VERSION 5.7 ;
  NOWIREEXTENSIONATPIN ON ;
  DIVIDERCHAR "/" ;
  BUSBITCHARS "[]" ;
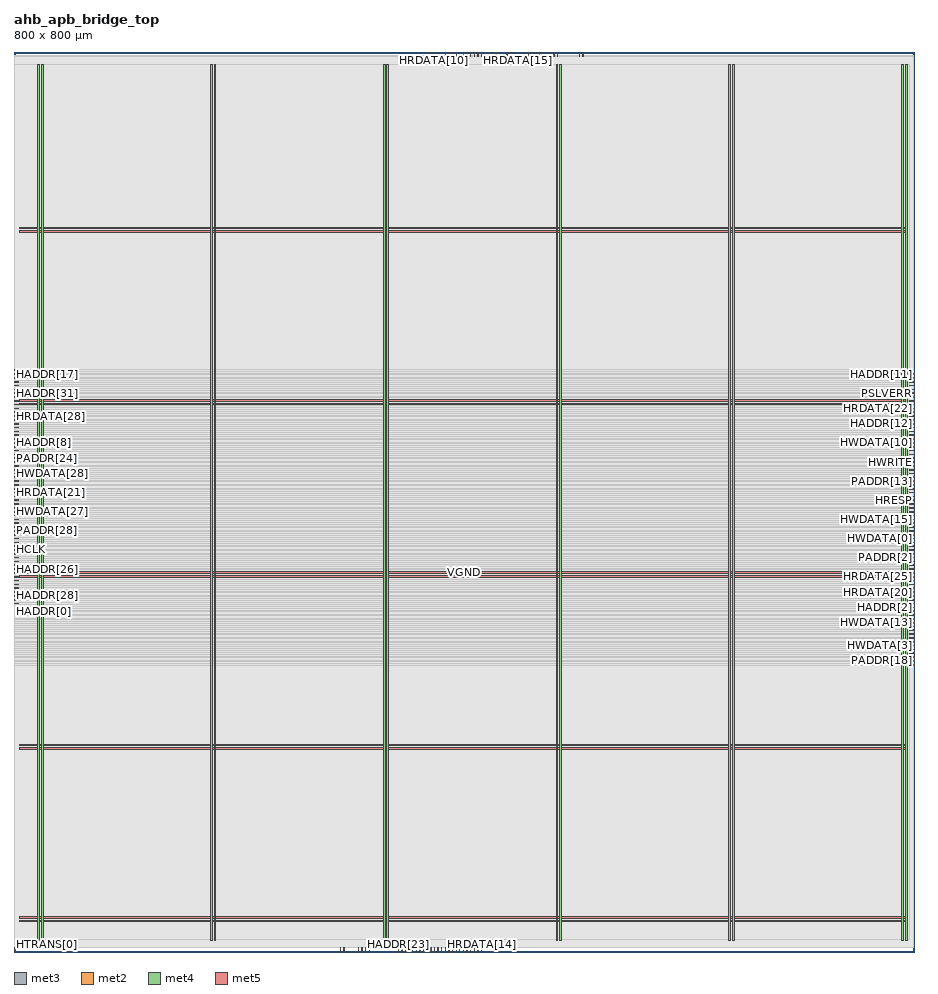
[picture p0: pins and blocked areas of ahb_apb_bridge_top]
MACRO ahb_apb_bridge_top
  CLASS BLOCK ;
  FOREIGN ahb_apb_bridge_top ;
  ORIGIN 0.000 0.000 ;
  SIZE 800.000 BY 800.000 ;
  PIN HADDR[0]
    DIRECTION INPUT ;
    USE SIGNAL ;
    ANTENNAGATEAREA 0.196500 ;
    PORT
      LAYER met3 ;
        RECT 0.000 309.440 4.000 310.040 ;
    END
  END HADDR[0]
  PIN HADDR[10]
    DIRECTION INPUT ;
    USE SIGNAL ;
    ANTENNAGATEAREA 0.196500 ;
    PORT
      LAYER met2 ;
        RECT 383.270 0.000 383.550 4.000 ;
    END
  END HADDR[10]
  PIN HADDR[11]
    DIRECTION INPUT ;
    USE SIGNAL ;
    ANTENNAGATEAREA 0.196500 ;
    PORT
      LAYER met3 ;
        RECT 796.000 513.440 800.000 514.040 ;
    END
  END HADDR[11]
  PIN HADDR[12]
    DIRECTION INPUT ;
    USE SIGNAL ;
    ANTENNAGATEAREA 0.196500 ;
    PORT
      LAYER met3 ;
        RECT 796.000 469.240 800.000 469.840 ;
    END
  END HADDR[12]
  PIN HADDR[13]
    DIRECTION INPUT ;
    USE SIGNAL ;
    ANTENNAGATEAREA 0.213000 ;
    PORT
      LAYER met2 ;
        RECT 463.770 796.000 464.050 800.000 ;
    END
  END HADDR[13]
  PIN HADDR[14]
    DIRECTION INPUT ;
    USE SIGNAL ;
    ANTENNAGATEAREA 0.196500 ;
    PORT
      LAYER met2 ;
        RECT 402.590 0.000 402.870 4.000 ;
    END
  END HADDR[14]
  PIN HADDR[15]
    DIRECTION INPUT ;
    USE SIGNAL ;
    ANTENNAGATEAREA 0.196500 ;
    PORT
      LAYER met3 ;
        RECT 0.000 516.840 4.000 517.440 ;
    END
  END HADDR[15]
  PIN HADDR[16]
    DIRECTION INPUT ;
    USE SIGNAL ;
    ANTENNAGATEAREA 0.196500 ;
    PORT
      LAYER met3 ;
        RECT 796.000 431.840 800.000 432.440 ;
    END
  END HADDR[16]
  PIN HADDR[17]
    DIRECTION INPUT ;
    USE SIGNAL ;
    ANTENNAGATEAREA 0.196500 ;
    PORT
      LAYER met3 ;
        RECT 0.000 513.440 4.000 514.040 ;
    END
  END HADDR[17]
  PIN HADDR[18]
    DIRECTION INPUT ;
    USE SIGNAL ;
    ANTENNAGATEAREA 0.196500 ;
    PORT
      LAYER met3 ;
        RECT 796.000 255.040 800.000 255.640 ;
    END
  END HADDR[18]
  PIN HADDR[19]
    DIRECTION INPUT ;
    USE SIGNAL ;
    ANTENNAGATEAREA 0.196500 ;
    PORT
      LAYER met3 ;
        RECT 796.000 278.840 800.000 279.440 ;
    END
  END HADDR[19]
  PIN HADDR[1]
    DIRECTION INPUT ;
    USE SIGNAL ;
    ANTENNAGATEAREA 0.196500 ;
    PORT
      LAYER met3 ;
        RECT 796.000 275.440 800.000 276.040 ;
    END
  END HADDR[1]
  PIN HADDR[20]
    DIRECTION INPUT ;
    USE SIGNAL ;
    ANTENNAGATEAREA 0.196500 ;
    PORT
      LAYER met2 ;
        RECT 370.390 796.000 370.670 800.000 ;
    END
  END HADDR[20]
  PIN HADDR[21]
    DIRECTION INPUT ;
    USE SIGNAL ;
    ANTENNAGATEAREA 0.196500 ;
    PORT
      LAYER met3 ;
        RECT 0.000 329.840 4.000 330.440 ;
    END
  END HADDR[21]
  PIN HADDR[22]
    DIRECTION INPUT ;
    USE SIGNAL ;
    ANTENNAGATEAREA 0.196500 ;
    PORT
      LAYER met3 ;
        RECT 796.000 309.440 800.000 310.040 ;
    END
  END HADDR[22]
  PIN HADDR[23]
    DIRECTION INPUT ;
    USE SIGNAL ;
    ANTENNAGATEAREA 0.196500 ;
    PORT
      LAYER met2 ;
        RECT 341.410 0.000 341.690 4.000 ;
    END
  END HADDR[23]
  PIN HADDR[24]
    DIRECTION INPUT ;
    USE SIGNAL ;
    ANTENNAGATEAREA 0.196500 ;
    PORT
      LAYER met3 ;
        RECT 0.000 465.840 4.000 466.440 ;
    END
  END HADDR[24]
  PIN HADDR[25]
    DIRECTION INPUT ;
    USE SIGNAL ;
    ANTENNAGATEAREA 0.196500 ;
    PORT
      LAYER met3 ;
        RECT 796.000 380.840 800.000 381.440 ;
    END
  END HADDR[25]
  PIN HADDR[26]
    DIRECTION INPUT ;
    USE SIGNAL ;
    ANTENNAGATEAREA 0.196500 ;
    PORT
      LAYER met3 ;
        RECT 0.000 340.040 4.000 340.640 ;
    END
  END HADDR[26]
  PIN HADDR[27]
    DIRECTION INPUT ;
    USE SIGNAL ;
    ANTENNAGATEAREA 0.196500 ;
    PORT
      LAYER met3 ;
        RECT 0.000 421.640 4.000 422.240 ;
    END
  END HADDR[27]
  PIN HADDR[28]
    DIRECTION INPUT ;
    USE SIGNAL ;
    ANTENNAGATEAREA 0.196500 ;
    PORT
      LAYER met3 ;
        RECT 0.000 316.240 4.000 316.840 ;
    END
  END HADDR[28]
  PIN HADDR[29]
    DIRECTION INPUT ;
    USE SIGNAL ;
    ANTENNAGATEAREA 0.196500 ;
    PORT
      LAYER met3 ;
        RECT 0.000 462.440 4.000 463.040 ;
    END
  END HADDR[29]
  PIN HADDR[2]
    DIRECTION INPUT ;
    USE SIGNAL ;
    ANTENNAGATEAREA 0.196500 ;
    PORT
      LAYER met3 ;
        RECT 796.000 306.040 800.000 306.640 ;
    END
  END HADDR[2]
  PIN HADDR[30]
    DIRECTION INPUT ;
    USE SIGNAL ;
    ANTENNAGATEAREA 0.196500 ;
    PORT
      LAYER met3 ;
        RECT 796.000 377.440 800.000 378.040 ;
    END
  END HADDR[30]
  PIN HADDR[31]
    DIRECTION INPUT ;
    USE SIGNAL ;
    ANTENNAGATEAREA 0.196500 ;
    PORT
      LAYER met3 ;
        RECT 0.000 503.240 4.000 503.840 ;
    END
  END HADDR[31]
  PIN HADDR[3]
    DIRECTION INPUT ;
    USE SIGNAL ;
    ANTENNAGATEAREA 0.196500 ;
    PORT
      LAYER met3 ;
        RECT 796.000 462.440 800.000 463.040 ;
    END
  END HADDR[3]
  PIN HADDR[4]
    DIRECTION INPUT ;
    USE SIGNAL ;
    ANTENNAGATEAREA 0.196500 ;
    PORT
      LAYER met3 ;
        RECT 796.000 404.640 800.000 405.240 ;
    END
  END HADDR[4]
  PIN HADDR[5]
    DIRECTION INPUT ;
    USE SIGNAL ;
    ANTENNAGATEAREA 0.196500 ;
    PORT
      LAYER met2 ;
        RECT 457.330 796.000 457.610 800.000 ;
    END
  END HADDR[5]
  PIN HADDR[6]
    DIRECTION INPUT ;
    USE SIGNAL ;
    ANTENNAGATEAREA 0.196500 ;
    PORT
      LAYER met3 ;
        RECT 0.000 448.840 4.000 449.440 ;
    END
  END HADDR[6]
  PIN HADDR[7]
    DIRECTION INPUT ;
    USE SIGNAL ;
    ANTENNAGATEAREA 0.196500 ;
    PORT
      LAYER met3 ;
        RECT 0.000 312.840 4.000 313.440 ;
    END
  END HADDR[7]
  PIN HADDR[8]
    DIRECTION INPUT ;
    USE SIGNAL ;
    ANTENNAGATEAREA 0.196500 ;
    PORT
      LAYER met3 ;
        RECT 0.000 452.240 4.000 452.840 ;
    END
  END HADDR[8]
  PIN HADDR[9]
    DIRECTION INPUT ;
    USE SIGNAL ;
    ANTENNAGATEAREA 0.196500 ;
    PORT
      LAYER met2 ;
        RECT 373.610 0.000 373.890 4.000 ;
    END
  END HADDR[9]
  PIN HCLK
    DIRECTION INPUT ;
    USE SIGNAL ;
    ANTENNAGATEAREA 0.852000 ;
    PORT
      LAYER met3 ;
        RECT 0.000 350.240 4.000 350.840 ;
    END
  END HCLK
  PIN HRDATA[0]
    DIRECTION OUTPUT ;
    USE SIGNAL ;
    ANTENNADIFFAREA 0.445500 ;
    PORT
      LAYER met2 ;
        RECT 315.650 0.000 315.930 4.000 ;
    END
  END HRDATA[0]
  PIN HRDATA[10]
    DIRECTION OUTPUT ;
    USE SIGNAL ;
    ANTENNADIFFAREA 0.445500 ;
    PORT
      LAYER met2 ;
        RECT 373.610 796.000 373.890 800.000 ;
    END
  END HRDATA[10]
  PIN HRDATA[11]
    DIRECTION OUTPUT ;
    USE SIGNAL ;
    ANTENNADIFFAREA 0.445500 ;
    PORT
      LAYER met3 ;
        RECT 0.000 499.840 4.000 500.440 ;
    END
  END HRDATA[11]
  PIN HRDATA[12]
    DIRECTION OUTPUT ;
    USE SIGNAL ;
    ANTENNADIFFAREA 0.445500 ;
    PORT
      LAYER met3 ;
        RECT 796.000 482.840 800.000 483.440 ;
    END
  END HRDATA[12]
  PIN HRDATA[13]
    DIRECTION OUTPUT ;
    USE SIGNAL ;
    ANTENNADIFFAREA 0.445500 ;
    PORT
      LAYER met3 ;
        RECT 0.000 414.840 4.000 415.440 ;
    END
  END HRDATA[13]
  PIN HRDATA[14]
    DIRECTION OUTPUT ;
    USE SIGNAL ;
    ANTENNADIFFAREA 0.445500 ;
    PORT
      LAYER met2 ;
        RECT 415.470 0.000 415.750 4.000 ;
    END
  END HRDATA[14]
  PIN HRDATA[15]
    DIRECTION OUTPUT ;
    USE SIGNAL ;
    ANTENNADIFFAREA 0.445500 ;
    PORT
      LAYER met2 ;
        RECT 447.670 796.000 447.950 800.000 ;
    END
  END HRDATA[15]
  PIN HRDATA[16]
    DIRECTION OUTPUT ;
    USE SIGNAL ;
    ANTENNADIFFAREA 0.445500 ;
    PORT
      LAYER met2 ;
        RECT 360.730 0.000 361.010 4.000 ;
    END
  END HRDATA[16]
  PIN HRDATA[17]
    DIRECTION OUTPUT ;
    USE SIGNAL ;
    ANTENNADIFFAREA 0.445500 ;
    PORT
      LAYER met3 ;
        RECT 796.000 438.640 800.000 439.240 ;
    END
  END HRDATA[17]
  PIN HRDATA[18]
    DIRECTION OUTPUT ;
    USE SIGNAL ;
    ANTENNADIFFAREA 0.445500 ;
    PORT
      LAYER met3 ;
        RECT 796.000 445.440 800.000 446.040 ;
    END
  END HRDATA[18]
  PIN HRDATA[19]
    DIRECTION OUTPUT ;
    USE SIGNAL ;
    ANTENNADIFFAREA 0.445500 ;
    PORT
      LAYER met2 ;
        RECT 470.210 796.000 470.490 800.000 ;
    END
  END HRDATA[19]
  PIN HRDATA[1]
    DIRECTION OUTPUT ;
    USE SIGNAL ;
    ANTENNADIFFAREA 0.445500 ;
    PORT
      LAYER met2 ;
        RECT 409.030 0.000 409.310 4.000 ;
    END
  END HRDATA[1]
  PIN HRDATA[20]
    DIRECTION OUTPUT ;
    USE SIGNAL ;
    ANTENNADIFFAREA 0.445500 ;
    PORT
      LAYER met3 ;
        RECT 796.000 312.840 800.000 313.440 ;
    END
  END HRDATA[20]
  PIN HRDATA[21]
    DIRECTION OUTPUT ;
    USE SIGNAL ;
    ANTENNADIFFAREA 0.445500 ;
    PORT
      LAYER met3 ;
        RECT 0.000 408.040 4.000 408.640 ;
    END
  END HRDATA[21]
  PIN HRDATA[22]
    DIRECTION OUTPUT ;
    USE SIGNAL ;
    ANTENNADIFFAREA 0.445500 ;
    PORT
      LAYER met3 ;
        RECT 796.000 476.040 800.000 476.640 ;
    END
  END HRDATA[22]
  PIN HRDATA[23]
    DIRECTION OUTPUT ;
    USE SIGNAL ;
    ANTENNADIFFAREA 0.445500 ;
    PORT
      LAYER met2 ;
        RECT 293.110 0.000 293.390 4.000 ;
    END
  END HRDATA[23]
  PIN HRDATA[24]
    DIRECTION OUTPUT ;
    USE SIGNAL ;
    ANTENNADIFFAREA 0.445500 ;
    PORT
      LAYER met2 ;
        RECT 376.830 796.000 377.110 800.000 ;
    END
  END HRDATA[24]
  PIN HRDATA[25]
    DIRECTION OUTPUT ;
    USE SIGNAL ;
    ANTENNADIFFAREA 0.445500 ;
    PORT
      LAYER met3 ;
        RECT 796.000 333.240 800.000 333.840 ;
    END
  END HRDATA[25]
  PIN HRDATA[26]
    DIRECTION OUTPUT ;
    USE SIGNAL ;
    ANTENNADIFFAREA 0.445500 ;
    PORT
      LAYER met2 ;
        RECT 483.090 796.000 483.370 800.000 ;
    END
  END HRDATA[26]
  PIN HRDATA[27]
    DIRECTION OUTPUT ;
    USE SIGNAL ;
    ANTENNADIFFAREA 0.445500 ;
    PORT
      LAYER met3 ;
        RECT 0.000 479.440 4.000 480.040 ;
    END
  END HRDATA[27]
  PIN HRDATA[28]
    DIRECTION OUTPUT ;
    USE SIGNAL ;
    ANTENNADIFFAREA 0.445500 ;
    PORT
      LAYER met3 ;
        RECT 0.000 476.040 4.000 476.640 ;
    END
  END HRDATA[28]
  PIN HRDATA[29]
    DIRECTION OUTPUT ;
    USE SIGNAL ;
    ANTENNADIFFAREA 0.445500 ;
    PORT
      LAYER met2 ;
        RECT 380.050 796.000 380.330 800.000 ;
    END
  END HRDATA[29]
  PIN HRDATA[2]
    DIRECTION OUTPUT ;
    USE SIGNAL ;
    ANTENNADIFFAREA 0.445500 ;
    PORT
      LAYER met2 ;
        RECT 479.870 796.000 480.150 800.000 ;
    END
  END HRDATA[2]
  PIN HRDATA[30]
    DIRECTION OUTPUT ;
    USE SIGNAL ;
    ANTENNADIFFAREA 0.445500 ;
    PORT
      LAYER met3 ;
        RECT 796.000 292.440 800.000 293.040 ;
    END
  END HRDATA[30]
  PIN HRDATA[31]
    DIRECTION OUTPUT ;
    USE SIGNAL ;
    ANTENNADIFFAREA 0.445500 ;
    PORT
      LAYER met2 ;
        RECT 389.710 796.000 389.990 800.000 ;
    END
  END HRDATA[31]
  PIN HRDATA[3]
    DIRECTION OUTPUT ;
    USE SIGNAL ;
    ANTENNADIFFAREA 0.445500 ;
    PORT
      LAYER met2 ;
        RECT 454.110 796.000 454.390 800.000 ;
    END
  END HRDATA[3]
  PIN HRDATA[4]
    DIRECTION OUTPUT ;
    USE SIGNAL ;
    ANTENNADIFFAREA 0.445500 ;
    PORT
      LAYER met3 ;
        RECT 796.000 336.640 800.000 337.240 ;
    END
  END HRDATA[4]
  PIN HRDATA[5]
    DIRECTION OUTPUT ;
    USE SIGNAL ;
    ANTENNADIFFAREA 0.445500 ;
    PORT
      LAYER met3 ;
        RECT 0.000 333.240 4.000 333.840 ;
    END
  END HRDATA[5]
  PIN HRDATA[6]
    DIRECTION OUTPUT ;
    USE SIGNAL ;
    ANTENNADIFFAREA 0.445500 ;
    PORT
      LAYER met2 ;
        RECT 383.270 796.000 383.550 800.000 ;
    END
  END HRDATA[6]
  PIN HRDATA[7]
    DIRECTION OUTPUT ;
    USE SIGNAL ;
    ANTENNADIFFAREA 0.445500 ;
    PORT
      LAYER met3 ;
        RECT 0.000 486.240 4.000 486.840 ;
    END
  END HRDATA[7]
  PIN HRDATA[8]
    DIRECTION OUTPUT ;
    USE SIGNAL ;
    ANTENNADIFFAREA 0.445500 ;
    PORT
      LAYER met2 ;
        RECT 312.430 0.000 312.710 4.000 ;
    END
  END HRDATA[8]
  PIN HRDATA[9]
    DIRECTION OUTPUT ;
    USE SIGNAL ;
    ANTENNADIFFAREA 0.445500 ;
    PORT
      LAYER met2 ;
        RECT 505.630 796.000 505.910 800.000 ;
    END
  END HRDATA[9]
  PIN HREADY
    DIRECTION INPUT ;
    USE SIGNAL ;
    ANTENNAGATEAREA 0.196500 ;
    PORT
      LAYER met3 ;
        RECT 796.000 510.040 800.000 510.640 ;
    END
  END HREADY
  PIN HREADYOUT
    DIRECTION OUTPUT ;
    USE SIGNAL ;
    ANTENNADIFFAREA 0.445500 ;
    PORT
      LAYER met3 ;
        RECT 796.000 465.840 800.000 466.440 ;
    END
  END HREADYOUT
  PIN HRESETn
    DIRECTION INPUT ;
    USE SIGNAL ;
    ANTENNAGATEAREA 0.196500 ;
    PORT
      LAYER met3 ;
        RECT 796.000 496.440 800.000 497.040 ;
    END
  END HRESETn
  PIN HRESP
    DIRECTION OUTPUT ;
    USE SIGNAL ;
    ANTENNADIFFAREA 0.445500 ;
    PORT
      LAYER met3 ;
        RECT 796.000 401.240 800.000 401.840 ;
    END
  END HRESP
  PIN HTRANS[0]
    DIRECTION INPUT ;
    USE SIGNAL ;
    PORT
      LAYER met2 ;
        RECT 0.090 0.000 0.370 4.000 ;
    END
  END HTRANS[0]
  PIN HTRANS[1]
    DIRECTION INPUT ;
    USE SIGNAL ;
    ANTENNAGATEAREA 0.196500 ;
    PORT
      LAYER met3 ;
        RECT 796.000 394.440 800.000 395.040 ;
    END
  END HTRANS[1]
  PIN HWDATA[0]
    DIRECTION INPUT ;
    USE SIGNAL ;
    ANTENNAGATEAREA 0.196500 ;
    PORT
      LAYER met3 ;
        RECT 796.000 367.240 800.000 367.840 ;
    END
  END HWDATA[0]
  PIN HWDATA[10]
    DIRECTION INPUT ;
    USE SIGNAL ;
    ANTENNAGATEAREA 0.196500 ;
    PORT
      LAYER met3 ;
        RECT 796.000 459.040 800.000 459.640 ;
    END
  END HWDATA[10]
  PIN HWDATA[11]
    DIRECTION INPUT ;
    USE SIGNAL ;
    ANTENNAGATEAREA 0.196500 ;
    PORT
      LAYER met3 ;
        RECT 796.000 258.440 800.000 259.040 ;
    END
  END HWDATA[11]
  PIN HWDATA[12]
    DIRECTION INPUT ;
    USE SIGNAL ;
    ANTENNAGATEAREA 0.213000 ;
    PORT
      LAYER met3 ;
        RECT 0.000 455.640 4.000 456.240 ;
    END
  END HWDATA[12]
  PIN HWDATA[13]
    DIRECTION INPUT ;
    USE SIGNAL ;
    ANTENNAGATEAREA 0.196500 ;
    PORT
      LAYER met3 ;
        RECT 796.000 299.240 800.000 299.840 ;
    END
  END HWDATA[13]
  PIN HWDATA[14]
    DIRECTION INPUT ;
    USE SIGNAL ;
    ANTENNAGATEAREA 0.196500 ;
    PORT
      LAYER met2 ;
        RECT 386.490 0.000 386.770 4.000 ;
    END
  END HWDATA[14]
  PIN HWDATA[15]
    DIRECTION INPUT ;
    USE SIGNAL ;
    ANTENNAGATEAREA 0.196500 ;
    PORT
      LAYER met3 ;
        RECT 796.000 391.040 800.000 391.640 ;
    END
  END HWDATA[15]
  PIN HWDATA[16]
    DIRECTION INPUT ;
    USE SIGNAL ;
    ANTENNAGATEAREA 0.196500 ;
    PORT
      LAYER met2 ;
        RECT 444.450 796.000 444.730 800.000 ;
    END
  END HWDATA[16]
  PIN HWDATA[17]
    DIRECTION INPUT ;
    USE SIGNAL ;
    ANTENNAGATEAREA 0.196500 ;
    PORT
      LAYER met2 ;
        RECT 412.250 796.000 412.530 800.000 ;
    END
  END HWDATA[17]
  PIN HWDATA[18]
    DIRECTION INPUT ;
    USE SIGNAL ;
    ANTENNAGATEAREA 0.196500 ;
    PORT
      LAYER met3 ;
        RECT 0.000 387.640 4.000 388.240 ;
    END
  END HWDATA[18]
  PIN HWDATA[19]
    DIRECTION INPUT ;
    USE SIGNAL ;
    ANTENNAGATEAREA 0.196500 ;
    PORT
      LAYER met2 ;
        RECT 380.050 0.000 380.330 4.000 ;
    END
  END HWDATA[19]
  PIN HWDATA[1]
    DIRECTION INPUT ;
    USE SIGNAL ;
    ANTENNAGATEAREA 0.196500 ;
    PORT
      LAYER met3 ;
        RECT 0.000 459.040 4.000 459.640 ;
    END
  END HWDATA[1]
  PIN HWDATA[20]
    DIRECTION INPUT ;
    USE SIGNAL ;
    ANTENNAGATEAREA 0.196500 ;
    PORT
      LAYER met2 ;
        RECT 351.070 0.000 351.350 4.000 ;
    END
  END HWDATA[20]
  PIN HWDATA[21]
    DIRECTION INPUT ;
    USE SIGNAL ;
    ANTENNAGATEAREA 0.196500 ;
    PORT
      LAYER met3 ;
        RECT 0.000 357.040 4.000 357.640 ;
    END
  END HWDATA[21]
  PIN HWDATA[22]
    DIRECTION INPUT ;
    USE SIGNAL ;
    ANTENNAGATEAREA 0.196500 ;
    PORT
      LAYER met3 ;
        RECT 0.000 394.440 4.000 395.040 ;
    END
  END HWDATA[22]
  PIN HWDATA[23]
    DIRECTION INPUT ;
    USE SIGNAL ;
    ANTENNAGATEAREA 0.196500 ;
    PORT
      LAYER met2 ;
        RECT 418.690 796.000 418.970 800.000 ;
    END
  END HWDATA[23]
  PIN HWDATA[24]
    DIRECTION INPUT ;
    USE SIGNAL ;
    ANTENNAGATEAREA 0.196500 ;
    PORT
      LAYER met3 ;
        RECT 0.000 326.440 4.000 327.040 ;
    END
  END HWDATA[24]
  PIN HWDATA[25]
    DIRECTION INPUT ;
    USE SIGNAL ;
    ANTENNAGATEAREA 0.196500 ;
    PORT
      LAYER met3 ;
        RECT 796.000 302.640 800.000 303.240 ;
    END
  END HWDATA[25]
  PIN HWDATA[26]
    DIRECTION INPUT ;
    USE SIGNAL ;
    ANTENNAGATEAREA 0.196500 ;
    PORT
      LAYER met2 ;
        RECT 460.550 796.000 460.830 800.000 ;
    END
  END HWDATA[26]
  PIN HWDATA[27]
    DIRECTION INPUT ;
    USE SIGNAL ;
    ANTENNAGATEAREA 0.196500 ;
    PORT
      LAYER met3 ;
        RECT 0.000 391.040 4.000 391.640 ;
    END
  END HWDATA[27]
  PIN HWDATA[28]
    DIRECTION INPUT ;
    USE SIGNAL ;
    ANTENNAGATEAREA 0.196500 ;
    PORT
      LAYER met3 ;
        RECT 0.000 418.240 4.000 418.840 ;
    END
  END HWDATA[28]
  PIN HWDATA[29]
    DIRECTION INPUT ;
    USE SIGNAL ;
    ANTENNAGATEAREA 0.196500 ;
    PORT
      LAYER met2 ;
        RECT 367.170 0.000 367.450 4.000 ;
    END
  END HWDATA[29]
  PIN HWDATA[2]
    DIRECTION INPUT ;
    USE SIGNAL ;
    ANTENNAGATEAREA 0.196500 ;
    PORT
      LAYER met3 ;
        RECT 796.000 316.240 800.000 316.840 ;
    END
  END HWDATA[2]
  PIN HWDATA[30]
    DIRECTION INPUT ;
    USE SIGNAL ;
    ANTENNAGATEAREA 0.196500 ;
    PORT
      LAYER met3 ;
        RECT 0.000 377.440 4.000 378.040 ;
    END
  END HWDATA[30]
  PIN HWDATA[31]
    DIRECTION INPUT ;
    USE SIGNAL ;
    ANTENNAGATEAREA 0.196500 ;
    PORT
      LAYER met3 ;
        RECT 0.000 343.440 4.000 344.040 ;
    END
  END HWDATA[31]
  PIN HWDATA[3]
    DIRECTION INPUT ;
    USE SIGNAL ;
    ANTENNAGATEAREA 0.196500 ;
    PORT
      LAYER met3 ;
        RECT 796.000 272.040 800.000 272.640 ;
    END
  END HWDATA[3]
  PIN HWDATA[4]
    DIRECTION INPUT ;
    USE SIGNAL ;
    ANTENNAGATEAREA 0.196500 ;
    PORT
      LAYER met2 ;
        RECT 344.630 0.000 344.910 4.000 ;
    END
  END HWDATA[4]
  PIN HWDATA[5]
    DIRECTION INPUT ;
    USE SIGNAL ;
    ANTENNAGATEAREA 0.196500 ;
    PORT
      LAYER met3 ;
        RECT 796.000 346.840 800.000 347.440 ;
    END
  END HWDATA[5]
  PIN HWDATA[6]
    DIRECTION INPUT ;
    USE SIGNAL ;
    ANTENNAGATEAREA 0.196500 ;
    PORT
      LAYER met3 ;
        RECT 0.000 472.640 4.000 473.240 ;
    END
  END HWDATA[6]
  PIN HWDATA[7]
    DIRECTION INPUT ;
    USE SIGNAL ;
    ANTENNAGATEAREA 0.196500 ;
    PORT
      LAYER met2 ;
        RECT 431.570 796.000 431.850 800.000 ;
    END
  END HWDATA[7]
  PIN HWDATA[8]
    DIRECTION INPUT ;
    USE SIGNAL ;
    ANTENNAGATEAREA 0.196500 ;
    PORT
      LAYER met3 ;
        RECT 796.000 374.040 800.000 374.640 ;
    END
  END HWDATA[8]
  PIN HWDATA[9]
    DIRECTION INPUT ;
    USE SIGNAL ;
    ANTENNAGATEAREA 0.196500 ;
    PORT
      LAYER met3 ;
        RECT 796.000 343.440 800.000 344.040 ;
    END
  END HWDATA[9]
  PIN HWRITE
    DIRECTION INPUT ;
    USE SIGNAL ;
    ANTENNAGATEAREA 0.196500 ;
    PORT
      LAYER met3 ;
        RECT 796.000 435.240 800.000 435.840 ;
    END
  END HWRITE
  PIN PADDR[0]
    DIRECTION OUTPUT ;
    USE SIGNAL ;
    ANTENNADIFFAREA 0.445500 ;
    PORT
      LAYER met3 ;
        RECT 0.000 397.840 4.000 398.440 ;
    END
  END PADDR[0]
  PIN PADDR[10]
    DIRECTION OUTPUT ;
    USE SIGNAL ;
    ANTENNADIFFAREA 0.445500 ;
    PORT
      LAYER met2 ;
        RECT 396.150 0.000 396.430 4.000 ;
    END
  END PADDR[10]
  PIN PADDR[11]
    DIRECTION OUTPUT ;
    USE SIGNAL ;
    ANTENNADIFFAREA 0.445500 ;
    PORT
      LAYER met3 ;
        RECT 796.000 421.640 800.000 422.240 ;
    END
  END PADDR[11]
  PIN PADDR[12]
    DIRECTION OUTPUT ;
    USE SIGNAL ;
    ANTENNADIFFAREA 0.445500 ;
    PORT
      LAYER met3 ;
        RECT 796.000 506.640 800.000 507.240 ;
    END
  END PADDR[12]
  PIN PADDR[13]
    DIRECTION OUTPUT ;
    USE SIGNAL ;
    ANTENNADIFFAREA 0.445500 ;
    PORT
      LAYER met3 ;
        RECT 796.000 418.240 800.000 418.840 ;
    END
  END PADDR[13]
  PIN PADDR[14]
    DIRECTION OUTPUT ;
    USE SIGNAL ;
    ANTENNADIFFAREA 0.445500 ;
    PORT
      LAYER met2 ;
        RECT 389.710 0.000 389.990 4.000 ;
    END
  END PADDR[14]
  PIN PADDR[15]
    DIRECTION OUTPUT ;
    USE SIGNAL ;
    ANTENNADIFFAREA 0.445500 ;
    PORT
      LAYER met3 ;
        RECT 0.000 404.640 4.000 405.240 ;
    END
  END PADDR[15]
  PIN PADDR[16]
    DIRECTION OUTPUT ;
    USE SIGNAL ;
    ANTENNADIFFAREA 0.445500 ;
    PORT
      LAYER met3 ;
        RECT 796.000 499.840 800.000 500.440 ;
    END
  END PADDR[16]
  PIN PADDR[17]
    DIRECTION OUTPUT ;
    USE SIGNAL ;
    ANTENNADIFFAREA 0.445500 ;
    PORT
      LAYER met3 ;
        RECT 0.000 469.240 4.000 469.840 ;
    END
  END PADDR[17]
  PIN PADDR[18]
    DIRECTION OUTPUT ;
    USE SIGNAL ;
    ANTENNADIFFAREA 0.445500 ;
    PORT
      LAYER met3 ;
        RECT 796.000 265.240 800.000 265.840 ;
    END
  END PADDR[18]
  PIN PADDR[19]
    DIRECTION OUTPUT ;
    USE SIGNAL ;
    ANTENNADIFFAREA 0.445500 ;
    PORT
      LAYER met3 ;
        RECT 796.000 370.640 800.000 371.240 ;
    END
  END PADDR[19]
  PIN PADDR[1]
    DIRECTION OUTPUT ;
    USE SIGNAL ;
    ANTENNADIFFAREA 0.445500 ;
    PORT
      LAYER met3 ;
        RECT 796.000 282.240 800.000 282.840 ;
    END
  END PADDR[1]
  PIN PADDR[20]
    DIRECTION OUTPUT ;
    USE SIGNAL ;
    ANTENNADIFFAREA 0.445500 ;
    PORT
      LAYER met2 ;
        RECT 409.030 796.000 409.310 800.000 ;
    END
  END PADDR[20]
  PIN PADDR[21]
    DIRECTION OUTPUT ;
    USE SIGNAL ;
    ANTENNADIFFAREA 0.445500 ;
    PORT
      LAYER met3 ;
        RECT 0.000 336.640 4.000 337.240 ;
    END
  END PADDR[21]
  PIN PADDR[22]
    DIRECTION OUTPUT ;
    USE SIGNAL ;
    ANTENNADIFFAREA 0.445500 ;
    PORT
      LAYER met3 ;
        RECT 796.000 353.640 800.000 354.240 ;
    END
  END PADDR[22]
  PIN PADDR[23]
    DIRECTION OUTPUT ;
    USE SIGNAL ;
    ANTENNADIFFAREA 0.445500 ;
    PORT
      LAYER met2 ;
        RECT 354.290 0.000 354.570 4.000 ;
    END
  END PADDR[23]
  PIN PADDR[24]
    DIRECTION OUTPUT ;
    USE SIGNAL ;
    ANTENNADIFFAREA 0.445500 ;
    PORT
      LAYER met3 ;
        RECT 0.000 445.440 4.000 446.040 ;
    END
  END PADDR[24]
  PIN PADDR[25]
    DIRECTION OUTPUT ;
    USE SIGNAL ;
    ANTENNADIFFAREA 0.445500 ;
    PORT
      LAYER met3 ;
        RECT 796.000 384.240 800.000 384.840 ;
    END
  END PADDR[25]
  PIN PADDR[26]
    DIRECTION OUTPUT ;
    USE SIGNAL ;
    ANTENNADIFFAREA 0.445500 ;
    PORT
      LAYER met3 ;
        RECT 0.000 323.040 4.000 323.640 ;
    END
  END PADDR[26]
  PIN PADDR[27]
    DIRECTION OUTPUT ;
    USE SIGNAL ;
    ANTENNADIFFAREA 0.445500 ;
    PORT
      LAYER met3 ;
        RECT 0.000 435.240 4.000 435.840 ;
    END
  END PADDR[27]
  PIN PADDR[28]
    DIRECTION OUTPUT ;
    USE SIGNAL ;
    ANTENNADIFFAREA 0.445500 ;
    PORT
      LAYER met3 ;
        RECT 0.000 374.040 4.000 374.640 ;
    END
  END PADDR[28]
  PIN PADDR[29]
    DIRECTION OUTPUT ;
    USE SIGNAL ;
    ANTENNADIFFAREA 0.445500 ;
    PORT
      LAYER met3 ;
        RECT 0.000 442.040 4.000 442.640 ;
    END
  END PADDR[29]
  PIN PADDR[2]
    DIRECTION OUTPUT ;
    USE SIGNAL ;
    ANTENNADIFFAREA 0.445500 ;
    PORT
      LAYER met3 ;
        RECT 796.000 350.240 800.000 350.840 ;
    END
  END PADDR[2]
  PIN PADDR[30]
    DIRECTION OUTPUT ;
    USE SIGNAL ;
    ANTENNADIFFAREA 0.445500 ;
    PORT
      LAYER met3 ;
        RECT 796.000 268.640 800.000 269.240 ;
    END
  END PADDR[30]
  PIN PADDR[31]
    DIRECTION OUTPUT ;
    USE SIGNAL ;
    ANTENNADIFFAREA 0.445500 ;
    PORT
      LAYER met3 ;
        RECT 0.000 510.040 4.000 510.640 ;
    END
  END PADDR[31]
  PIN PADDR[3]
    DIRECTION OUTPUT ;
    USE SIGNAL ;
    ANTENNADIFFAREA 0.445500 ;
    PORT
      LAYER met3 ;
        RECT 796.000 411.440 800.000 412.040 ;
    END
  END PADDR[3]
  PIN PADDR[4]
    DIRECTION OUTPUT ;
    USE SIGNAL ;
    ANTENNADIFFAREA 0.445500 ;
    PORT
      LAYER met3 ;
        RECT 796.000 387.640 800.000 388.240 ;
    END
  END PADDR[4]
  PIN PADDR[5]
    DIRECTION OUTPUT ;
    USE SIGNAL ;
    ANTENNADIFFAREA 0.445500 ;
    PORT
      LAYER met2 ;
        RECT 425.130 796.000 425.410 800.000 ;
    END
  END PADDR[5]
  PIN PADDR[6]
    DIRECTION OUTPUT ;
    USE SIGNAL ;
    ANTENNADIFFAREA 0.445500 ;
    PORT
      LAYER met3 ;
        RECT 0.000 428.440 4.000 429.040 ;
    END
  END PADDR[6]
  PIN PADDR[7]
    DIRECTION OUTPUT ;
    USE SIGNAL ;
    ANTENNADIFFAREA 0.445500 ;
    PORT
      LAYER met3 ;
        RECT 0.000 370.640 4.000 371.240 ;
    END
  END PADDR[7]
  PIN PADDR[8]
    DIRECTION OUTPUT ;
    USE SIGNAL ;
    ANTENNADIFFAREA 0.445500 ;
    PORT
      LAYER met3 ;
        RECT 0.000 431.840 4.000 432.440 ;
    END
  END PADDR[8]
  PIN PADDR[9]
    DIRECTION OUTPUT ;
    USE SIGNAL ;
    ANTENNADIFFAREA 0.445500 ;
    PORT
      LAYER met2 ;
        RECT 376.830 0.000 377.110 4.000 ;
    END
  END PADDR[9]
  PIN PENABLE
    DIRECTION OUTPUT ;
    USE SIGNAL ;
    ANTENNADIFFAREA 0.445500 ;
    PORT
      LAYER met3 ;
        RECT 796.000 442.040 800.000 442.640 ;
    END
  END PENABLE
  PIN PRDATA[0]
    DIRECTION INPUT ;
    USE SIGNAL ;
    ANTENNAGATEAREA 0.196500 ;
    PORT
      LAYER met2 ;
        RECT 309.210 0.000 309.490 4.000 ;
    END
  END PRDATA[0]
  PIN PRDATA[10]
    DIRECTION INPUT ;
    USE SIGNAL ;
    ANTENNAGATEAREA 0.196500 ;
    PORT
      LAYER met2 ;
        RECT 399.370 796.000 399.650 800.000 ;
    END
  END PRDATA[10]
  PIN PRDATA[11]
    DIRECTION INPUT ;
    USE SIGNAL ;
    ANTENNAGATEAREA 0.196500 ;
    PORT
      LAYER met3 ;
        RECT 0.000 489.640 4.000 490.240 ;
    END
  END PRDATA[11]
  PIN PRDATA[12]
    DIRECTION INPUT ;
    USE SIGNAL ;
    ANTENNAGATEAREA 0.196500 ;
    PORT
      LAYER met3 ;
        RECT 796.000 448.840 800.000 449.440 ;
    END
  END PRDATA[12]
  PIN PRDATA[13]
    DIRECTION INPUT ;
    USE SIGNAL ;
    ANTENNAGATEAREA 0.196500 ;
    PORT
      LAYER met3 ;
        RECT 0.000 411.440 4.000 412.040 ;
    END
  END PRDATA[13]
  PIN PRDATA[14]
    DIRECTION INPUT ;
    USE SIGNAL ;
    ANTENNAGATEAREA 0.196500 ;
    PORT
      LAYER met2 ;
        RECT 412.250 0.000 412.530 4.000 ;
    END
  END PRDATA[14]
  PIN PRDATA[15]
    DIRECTION INPUT ;
    USE SIGNAL ;
    ANTENNAGATEAREA 0.196500 ;
    PORT
      LAYER met2 ;
        RECT 441.230 796.000 441.510 800.000 ;
    END
  END PRDATA[15]
  PIN PRDATA[16]
    DIRECTION INPUT ;
    USE SIGNAL ;
    ANTENNAGATEAREA 0.196500 ;
    PORT
      LAYER met2 ;
        RECT 363.950 0.000 364.230 4.000 ;
    END
  END PRDATA[16]
  PIN PRDATA[17]
    DIRECTION INPUT ;
    USE SIGNAL ;
    ANTENNAGATEAREA 0.196500 ;
    PORT
      LAYER met3 ;
        RECT 796.000 414.840 800.000 415.440 ;
    END
  END PRDATA[17]
  PIN PRDATA[18]
    DIRECTION INPUT ;
    USE SIGNAL ;
    ANTENNAGATEAREA 0.196500 ;
    PORT
      LAYER met3 ;
        RECT 796.000 479.440 800.000 480.040 ;
    END
  END PRDATA[18]
  PIN PRDATA[19]
    DIRECTION INPUT ;
    USE SIGNAL ;
    ANTENNAGATEAREA 0.196500 ;
    PORT
      LAYER met2 ;
        RECT 466.990 796.000 467.270 800.000 ;
    END
  END PRDATA[19]
  PIN PRDATA[1]
    DIRECTION INPUT ;
    USE SIGNAL ;
    ANTENNAGATEAREA 0.196500 ;
    PORT
      LAYER met2 ;
        RECT 405.810 0.000 406.090 4.000 ;
    END
  END PRDATA[1]
  PIN PRDATA[20]
    DIRECTION INPUT ;
    USE SIGNAL ;
    ANTENNAGATEAREA 0.196500 ;
    PORT
      LAYER met3 ;
        RECT 796.000 326.440 800.000 327.040 ;
    END
  END PRDATA[20]
  PIN PRDATA[21]
    DIRECTION INPUT ;
    USE SIGNAL ;
    ANTENNAGATEAREA 0.196500 ;
    PORT
      LAYER met3 ;
        RECT 0.000 346.840 4.000 347.440 ;
    END
  END PRDATA[21]
  PIN PRDATA[22]
    DIRECTION INPUT ;
    USE SIGNAL ;
    ANTENNAGATEAREA 0.196500 ;
    PORT
      LAYER met3 ;
        RECT 796.000 452.240 800.000 452.840 ;
    END
  END PRDATA[22]
  PIN PRDATA[23]
    DIRECTION INPUT ;
    USE SIGNAL ;
    ANTENNAGATEAREA 0.196500 ;
    PORT
      LAYER met2 ;
        RECT 289.890 0.000 290.170 4.000 ;
    END
  END PRDATA[23]
  PIN PRDATA[24]
    DIRECTION INPUT ;
    USE SIGNAL ;
    ANTENNAGATEAREA 0.196500 ;
    PORT
      LAYER met2 ;
        RECT 402.590 796.000 402.870 800.000 ;
    END
  END PRDATA[24]
  PIN PRDATA[25]
    DIRECTION INPUT ;
    USE SIGNAL ;
    ANTENNAGATEAREA 0.196500 ;
    PORT
      LAYER met3 ;
        RECT 796.000 329.840 800.000 330.440 ;
    END
  END PRDATA[25]
  PIN PRDATA[26]
    DIRECTION INPUT ;
    USE SIGNAL ;
    ANTENNAGATEAREA 0.196500 ;
    PORT
      LAYER met2 ;
        RECT 473.430 796.000 473.710 800.000 ;
    END
  END PRDATA[26]
  PIN PRDATA[27]
    DIRECTION INPUT ;
    USE SIGNAL ;
    ANTENNAGATEAREA 0.196500 ;
    PORT
      LAYER met3 ;
        RECT 0.000 493.040 4.000 493.640 ;
    END
  END PRDATA[27]
  PIN PRDATA[28]
    DIRECTION INPUT ;
    USE SIGNAL ;
    ANTENNAGATEAREA 0.196500 ;
    PORT
      LAYER met3 ;
        RECT 0.000 496.440 4.000 497.040 ;
    END
  END PRDATA[28]
  PIN PRDATA[29]
    DIRECTION INPUT ;
    USE SIGNAL ;
    ANTENNAGATEAREA 0.196500 ;
    PORT
      LAYER met2 ;
        RECT 396.150 796.000 396.430 800.000 ;
    END
  END PRDATA[29]
  PIN PRDATA[2]
    DIRECTION INPUT ;
    USE SIGNAL ;
    ANTENNAGATEAREA 0.196500 ;
    PORT
      LAYER met2 ;
        RECT 476.650 796.000 476.930 800.000 ;
    END
  END PRDATA[2]
  PIN PRDATA[30]
    DIRECTION INPUT ;
    USE SIGNAL ;
    ANTENNAGATEAREA 0.196500 ;
    PORT
      LAYER met3 ;
        RECT 796.000 295.840 800.000 296.440 ;
    END
  END PRDATA[30]
  PIN PRDATA[31]
    DIRECTION INPUT ;
    USE SIGNAL ;
    ANTENNAGATEAREA 0.196500 ;
    PORT
      LAYER met2 ;
        RECT 392.930 796.000 393.210 800.000 ;
    END
  END PRDATA[31]
  PIN PRDATA[3]
    DIRECTION INPUT ;
    USE SIGNAL ;
    ANTENNAGATEAREA 0.196500 ;
    PORT
      LAYER met2 ;
        RECT 450.890 796.000 451.170 800.000 ;
    END
  END PRDATA[3]
  PIN PRDATA[4]
    DIRECTION INPUT ;
    USE SIGNAL ;
    ANTENNAGATEAREA 0.196500 ;
    PORT
      LAYER met3 ;
        RECT 796.000 363.840 800.000 364.440 ;
    END
  END PRDATA[4]
  PIN PRDATA[5]
    DIRECTION INPUT ;
    USE SIGNAL ;
    ANTENNAGATEAREA 0.196500 ;
    PORT
      LAYER met3 ;
        RECT 0.000 360.440 4.000 361.040 ;
    END
  END PRDATA[5]
  PIN PRDATA[6]
    DIRECTION INPUT ;
    USE SIGNAL ;
    ANTENNAGATEAREA 0.196500 ;
    PORT
      LAYER met2 ;
        RECT 386.490 796.000 386.770 800.000 ;
    END
  END PRDATA[6]
  PIN PRDATA[7]
    DIRECTION INPUT ;
    USE SIGNAL ;
    ANTENNAGATEAREA 0.196500 ;
    PORT
      LAYER met3 ;
        RECT 0.000 482.840 4.000 483.440 ;
    END
  END PRDATA[7]
  PIN PRDATA[8]
    DIRECTION INPUT ;
    USE SIGNAL ;
    ANTENNAGATEAREA 0.196500 ;
    PORT
      LAYER met2 ;
        RECT 305.990 0.000 306.270 4.000 ;
    END
  END PRDATA[8]
  PIN PRDATA[9]
    DIRECTION INPUT ;
    USE SIGNAL ;
    ANTENNAGATEAREA 0.196500 ;
    PORT
      LAYER met2 ;
        RECT 502.410 796.000 502.690 800.000 ;
    END
  END PRDATA[9]
  PIN PREADY
    DIRECTION INPUT ;
    USE SIGNAL ;
    ANTENNAGATEAREA 0.196500 ;
    PORT
      LAYER met3 ;
        RECT 796.000 486.240 800.000 486.840 ;
    END
  END PREADY
  PIN PSEL[0]
    DIRECTION OUTPUT ;
    USE SIGNAL ;
    ANTENNADIFFAREA 0.445500 ;
    PORT
      LAYER met3 ;
        RECT 796.000 489.640 800.000 490.240 ;
    END
  END PSEL[0]
  PIN PSEL[1]
    DIRECTION OUTPUT ;
    USE SIGNAL ;
    ANTENNADIFFAREA 0.445500 ;
    PORT
      LAYER met3 ;
        RECT 796.000 455.640 800.000 456.240 ;
    END
  END PSEL[1]
  PIN PSEL[2]
    DIRECTION OUTPUT ;
    USE SIGNAL ;
    ANTENNADIFFAREA 0.445500 ;
    PORT
      LAYER met3 ;
        RECT 796.000 428.440 800.000 429.040 ;
    END
  END PSEL[2]
  PIN PSEL[3]
    DIRECTION OUTPUT ;
    USE SIGNAL ;
    ANTENNADIFFAREA 0.445500 ;
    PORT
      LAYER met3 ;
        RECT 796.000 472.640 800.000 473.240 ;
    END
  END PSEL[3]
  PIN PSLVERR
    DIRECTION INPUT ;
    USE SIGNAL ;
    ANTENNAGATEAREA 0.196500 ;
    PORT
      LAYER met3 ;
        RECT 796.000 503.240 800.000 503.840 ;
    END
  END PSLVERR
  PIN PWDATA[0]
    DIRECTION OUTPUT ;
    USE SIGNAL ;
    ANTENNADIFFAREA 0.445500 ;
    PORT
      LAYER met3 ;
        RECT 796.000 319.640 800.000 320.240 ;
    END
  END PWDATA[0]
  PIN PWDATA[10]
    DIRECTION OUTPUT ;
    USE SIGNAL ;
    ANTENNADIFFAREA 0.445500 ;
    PORT
      LAYER met3 ;
        RECT 796.000 425.040 800.000 425.640 ;
    END
  END PWDATA[10]
  PIN PWDATA[11]
    DIRECTION OUTPUT ;
    USE SIGNAL ;
    ANTENNADIFFAREA 0.445500 ;
    PORT
      LAYER met3 ;
        RECT 796.000 397.840 800.000 398.440 ;
    END
  END PWDATA[11]
  PIN PWDATA[12]
    DIRECTION OUTPUT ;
    USE SIGNAL ;
    ANTENNADIFFAREA 0.445500 ;
    PORT
      LAYER met2 ;
        RECT 405.810 796.000 406.090 800.000 ;
    END
  END PWDATA[12]
  PIN PWDATA[13]
    DIRECTION OUTPUT ;
    USE SIGNAL ;
    ANTENNADIFFAREA 0.445500 ;
    PORT
      LAYER met3 ;
        RECT 796.000 289.040 800.000 289.640 ;
    END
  END PWDATA[13]
  PIN PWDATA[14]
    DIRECTION OUTPUT ;
    USE SIGNAL ;
    ANTENNADIFFAREA 0.445500 ;
    PORT
      LAYER met2 ;
        RECT 399.370 0.000 399.650 4.000 ;
    END
  END PWDATA[14]
  PIN PWDATA[15]
    DIRECTION OUTPUT ;
    USE SIGNAL ;
    ANTENNADIFFAREA 0.445500 ;
    PORT
      LAYER met3 ;
        RECT 796.000 408.040 800.000 408.640 ;
    END
  END PWDATA[15]
  PIN PWDATA[16]
    DIRECTION OUTPUT ;
    USE SIGNAL ;
    ANTENNADIFFAREA 0.445500 ;
    PORT
      LAYER met2 ;
        RECT 438.010 796.000 438.290 800.000 ;
    END
  END PWDATA[16]
  PIN PWDATA[17]
    DIRECTION OUTPUT ;
    USE SIGNAL ;
    ANTENNADIFFAREA 0.445500 ;
    PORT
      LAYER met2 ;
        RECT 415.470 796.000 415.750 800.000 ;
    END
  END PWDATA[17]
  PIN PWDATA[18]
    DIRECTION OUTPUT ;
    USE SIGNAL ;
    ANTENNADIFFAREA 0.445500 ;
    PORT
      LAYER met3 ;
        RECT 0.000 363.840 4.000 364.440 ;
    END
  END PWDATA[18]
  PIN PWDATA[19]
    DIRECTION OUTPUT ;
    USE SIGNAL ;
    ANTENNADIFFAREA 0.445500 ;
    PORT
      LAYER met2 ;
        RECT 392.930 0.000 393.210 4.000 ;
    END
  END PWDATA[19]
  PIN PWDATA[1]
    DIRECTION OUTPUT ;
    USE SIGNAL ;
    ANTENNADIFFAREA 0.445500 ;
    PORT
      LAYER met3 ;
        RECT 0.000 438.640 4.000 439.240 ;
    END
  END PWDATA[1]
  PIN PWDATA[20]
    DIRECTION OUTPUT ;
    USE SIGNAL ;
    ANTENNADIFFAREA 0.445500 ;
    PORT
      LAYER met2 ;
        RECT 347.850 0.000 348.130 4.000 ;
    END
  END PWDATA[20]
  PIN PWDATA[21]
    DIRECTION OUTPUT ;
    USE SIGNAL ;
    ANTENNADIFFAREA 0.445500 ;
    PORT
      LAYER met3 ;
        RECT 0.000 401.240 4.000 401.840 ;
    END
  END PWDATA[21]
  PIN PWDATA[22]
    DIRECTION OUTPUT ;
    USE SIGNAL ;
    ANTENNADIFFAREA 0.445500 ;
    PORT
      LAYER met3 ;
        RECT 0.000 384.240 4.000 384.840 ;
    END
  END PWDATA[22]
  PIN PWDATA[23]
    DIRECTION OUTPUT ;
    USE SIGNAL ;
    ANTENNADIFFAREA 0.445500 ;
    PORT
      LAYER met2 ;
        RECT 421.910 796.000 422.190 800.000 ;
    END
  END PWDATA[23]
  PIN PWDATA[24]
    DIRECTION OUTPUT ;
    USE SIGNAL ;
    ANTENNADIFFAREA 0.445500 ;
    PORT
      LAYER met3 ;
        RECT 0.000 367.240 4.000 367.840 ;
    END
  END PWDATA[24]
  PIN PWDATA[25]
    DIRECTION OUTPUT ;
    USE SIGNAL ;
    ANTENNADIFFAREA 0.445500 ;
    PORT
      LAYER met3 ;
        RECT 796.000 357.040 800.000 357.640 ;
    END
  END PWDATA[25]
  PIN PWDATA[26]
    DIRECTION OUTPUT ;
    USE SIGNAL ;
    ANTENNADIFFAREA 0.445500 ;
    PORT
      LAYER met2 ;
        RECT 428.350 796.000 428.630 800.000 ;
    END
  END PWDATA[26]
  PIN PWDATA[27]
    DIRECTION OUTPUT ;
    USE SIGNAL ;
    ANTENNADIFFAREA 0.445500 ;
    PORT
      LAYER met3 ;
        RECT 0.000 353.640 4.000 354.240 ;
    END
  END PWDATA[27]
  PIN PWDATA[28]
    DIRECTION OUTPUT ;
    USE SIGNAL ;
    ANTENNADIFFAREA 0.445500 ;
    PORT
      LAYER met3 ;
        RECT 0.000 506.640 4.000 507.240 ;
    END
  END PWDATA[28]
  PIN PWDATA[29]
    DIRECTION OUTPUT ;
    USE SIGNAL ;
    ANTENNADIFFAREA 0.445500 ;
    PORT
      LAYER met2 ;
        RECT 357.510 0.000 357.790 4.000 ;
    END
  END PWDATA[29]
  PIN PWDATA[2]
    DIRECTION OUTPUT ;
    USE SIGNAL ;
    ANTENNADIFFAREA 0.445500 ;
    PORT
      LAYER met3 ;
        RECT 796.000 360.440 800.000 361.040 ;
    END
  END PWDATA[2]
  PIN PWDATA[30]
    DIRECTION OUTPUT ;
    USE SIGNAL ;
    ANTENNADIFFAREA 0.445500 ;
    PORT
      LAYER met3 ;
        RECT 0.000 380.840 4.000 381.440 ;
    END
  END PWDATA[30]
  PIN PWDATA[31]
    DIRECTION OUTPUT ;
    USE SIGNAL ;
    ANTENNADIFFAREA 0.445500 ;
    PORT
      LAYER met3 ;
        RECT 0.000 319.640 4.000 320.240 ;
    END
  END PWDATA[31]
  PIN PWDATA[3]
    DIRECTION OUTPUT ;
    USE SIGNAL ;
    ANTENNADIFFAREA 0.445500 ;
    PORT
      LAYER met3 ;
        RECT 796.000 261.840 800.000 262.440 ;
    END
  END PWDATA[3]
  PIN PWDATA[4]
    DIRECTION OUTPUT ;
    USE SIGNAL ;
    ANTENNADIFFAREA 0.445500 ;
    PORT
      LAYER met2 ;
        RECT 370.390 0.000 370.670 4.000 ;
    END
  END PWDATA[4]
  PIN PWDATA[5]
    DIRECTION OUTPUT ;
    USE SIGNAL ;
    ANTENNADIFFAREA 0.445500 ;
    PORT
      LAYER met3 ;
        RECT 796.000 323.040 800.000 323.640 ;
    END
  END PWDATA[5]
  PIN PWDATA[6]
    DIRECTION OUTPUT ;
    USE SIGNAL ;
    ANTENNADIFFAREA 0.445500 ;
    PORT
      LAYER met3 ;
        RECT 0.000 425.040 4.000 425.640 ;
    END
  END PWDATA[6]
  PIN PWDATA[7]
    DIRECTION OUTPUT ;
    USE SIGNAL ;
    ANTENNADIFFAREA 0.445500 ;
    PORT
      LAYER met2 ;
        RECT 434.790 796.000 435.070 800.000 ;
    END
  END PWDATA[7]
  PIN PWDATA[8]
    DIRECTION OUTPUT ;
    USE SIGNAL ;
    ANTENNADIFFAREA 0.445500 ;
    PORT
      LAYER met3 ;
        RECT 796.000 285.640 800.000 286.240 ;
    END
  END PWDATA[8]
  PIN PWDATA[9]
    DIRECTION OUTPUT ;
    USE SIGNAL ;
    ANTENNADIFFAREA 0.445500 ;
    PORT
      LAYER met3 ;
        RECT 796.000 340.040 800.000 340.640 ;
    END
  END PWDATA[9]
  PIN PWRITE
    DIRECTION OUTPUT ;
    USE SIGNAL ;
    ANTENNADIFFAREA 0.445500 ;
    PORT
      LAYER met3 ;
        RECT 796.000 493.040 800.000 493.640 ;
    END
  END PWRITE
  PIN VGND
    DIRECTION INOUT ;
    USE GROUND ;
    PORT
      LAYER met4 ;
        RECT 24.340 10.640 25.940 789.040 ;
    END
    PORT
      LAYER met4 ;
        RECT 177.940 10.640 179.540 789.040 ;
    END
    PORT
      LAYER met4 ;
        RECT 331.540 10.640 333.140 789.040 ;
    END
    PORT
      LAYER met4 ;
        RECT 485.140 10.640 486.740 789.040 ;
    END
    PORT
      LAYER met4 ;
        RECT 638.740 10.640 640.340 789.040 ;
    END
    PORT
      LAYER met4 ;
        RECT 792.340 10.640 793.940 789.040 ;
    END
    PORT
      LAYER met5 ;
        RECT 5.280 30.030 794.660 31.630 ;
    END
    PORT
      LAYER met5 ;
        RECT 5.280 183.210 794.660 184.810 ;
    END
    PORT
      LAYER met5 ;
        RECT 5.280 336.390 794.660 337.990 ;
    END
    PORT
      LAYER met5 ;
        RECT 5.280 489.570 794.660 491.170 ;
    END
    PORT
      LAYER met5 ;
        RECT 5.280 642.750 794.660 644.350 ;
    END
  END VGND
  PIN VPWR
    DIRECTION INOUT ;
    USE POWER ;
    PORT
      LAYER met4 ;
        RECT 21.040 10.640 22.640 789.040 ;
    END
    PORT
      LAYER met4 ;
        RECT 174.640 10.640 176.240 789.040 ;
    END
    PORT
      LAYER met4 ;
        RECT 328.240 10.640 329.840 789.040 ;
    END
    PORT
      LAYER met4 ;
        RECT 481.840 10.640 483.440 789.040 ;
    END
    PORT
      LAYER met4 ;
        RECT 635.440 10.640 637.040 789.040 ;
    END
    PORT
      LAYER met4 ;
        RECT 789.040 10.640 790.640 789.040 ;
    END
    PORT
      LAYER met5 ;
        RECT 5.280 26.730 794.660 28.330 ;
    END
    PORT
      LAYER met5 ;
        RECT 5.280 179.910 794.660 181.510 ;
    END
    PORT
      LAYER met5 ;
        RECT 5.280 333.090 794.660 334.690 ;
    END
    PORT
      LAYER met5 ;
        RECT 5.280 486.270 794.660 487.870 ;
    END
    PORT
      LAYER met5 ;
        RECT 5.280 639.450 794.660 641.050 ;
    END
  END VPWR
  OBS
      LAYER nwell ;
        RECT 5.330 10.795 794.610 788.885 ;
      LAYER li1 ;
        RECT 5.520 10.795 794.420 788.885 ;
      LAYER met1 ;
        RECT 0.530 10.240 799.410 789.040 ;
      LAYER met2 ;
        RECT 0.550 795.720 370.110 796.690 ;
        RECT 370.950 795.720 373.330 796.690 ;
        RECT 374.170 795.720 376.550 796.690 ;
        RECT 377.390 795.720 379.770 796.690 ;
        RECT 380.610 795.720 382.990 796.690 ;
        RECT 383.830 795.720 386.210 796.690 ;
        RECT 387.050 795.720 389.430 796.690 ;
        RECT 390.270 795.720 392.650 796.690 ;
        RECT 393.490 795.720 395.870 796.690 ;
        RECT 396.710 795.720 399.090 796.690 ;
        RECT 399.930 795.720 402.310 796.690 ;
        RECT 403.150 795.720 405.530 796.690 ;
        RECT 406.370 795.720 408.750 796.690 ;
        RECT 409.590 795.720 411.970 796.690 ;
        RECT 412.810 795.720 415.190 796.690 ;
        RECT 416.030 795.720 418.410 796.690 ;
        RECT 419.250 795.720 421.630 796.690 ;
        RECT 422.470 795.720 424.850 796.690 ;
        RECT 425.690 795.720 428.070 796.690 ;
        RECT 428.910 795.720 431.290 796.690 ;
        RECT 432.130 795.720 434.510 796.690 ;
        RECT 435.350 795.720 437.730 796.690 ;
        RECT 438.570 795.720 440.950 796.690 ;
        RECT 441.790 795.720 444.170 796.690 ;
        RECT 445.010 795.720 447.390 796.690 ;
        RECT 448.230 795.720 450.610 796.690 ;
        RECT 451.450 795.720 453.830 796.690 ;
        RECT 454.670 795.720 457.050 796.690 ;
        RECT 457.890 795.720 460.270 796.690 ;
        RECT 461.110 795.720 463.490 796.690 ;
        RECT 464.330 795.720 466.710 796.690 ;
        RECT 467.550 795.720 469.930 796.690 ;
        RECT 470.770 795.720 473.150 796.690 ;
        RECT 473.990 795.720 476.370 796.690 ;
        RECT 477.210 795.720 479.590 796.690 ;
        RECT 480.430 795.720 482.810 796.690 ;
        RECT 483.650 795.720 502.130 796.690 ;
        RECT 502.970 795.720 505.350 796.690 ;
        RECT 506.190 795.720 799.380 796.690 ;
        RECT 0.550 4.280 799.380 795.720 ;
        RECT 0.650 4.000 289.610 4.280 ;
        RECT 290.450 4.000 292.830 4.280 ;
        RECT 293.670 4.000 305.710 4.280 ;
        RECT 306.550 4.000 308.930 4.280 ;
        RECT 309.770 4.000 312.150 4.280 ;
        RECT 312.990 4.000 315.370 4.280 ;
        RECT 316.210 4.000 341.130 4.280 ;
        RECT 341.970 4.000 344.350 4.280 ;
        RECT 345.190 4.000 347.570 4.280 ;
        RECT 348.410 4.000 350.790 4.280 ;
        RECT 351.630 4.000 354.010 4.280 ;
        RECT 354.850 4.000 357.230 4.280 ;
        RECT 358.070 4.000 360.450 4.280 ;
        RECT 361.290 4.000 363.670 4.280 ;
        RECT 364.510 4.000 366.890 4.280 ;
        RECT 367.730 4.000 370.110 4.280 ;
        RECT 370.950 4.000 373.330 4.280 ;
        RECT 374.170 4.000 376.550 4.280 ;
        RECT 377.390 4.000 379.770 4.280 ;
        RECT 380.610 4.000 382.990 4.280 ;
        RECT 383.830 4.000 386.210 4.280 ;
        RECT 387.050 4.000 389.430 4.280 ;
        RECT 390.270 4.000 392.650 4.280 ;
        RECT 393.490 4.000 395.870 4.280 ;
        RECT 396.710 4.000 399.090 4.280 ;
        RECT 399.930 4.000 402.310 4.280 ;
        RECT 403.150 4.000 405.530 4.280 ;
        RECT 406.370 4.000 408.750 4.280 ;
        RECT 409.590 4.000 411.970 4.280 ;
        RECT 412.810 4.000 415.190 4.280 ;
        RECT 416.030 4.000 799.380 4.280 ;
      LAYER met3 ;
        RECT 0.525 517.840 796.000 788.965 ;
        RECT 4.400 516.440 796.000 517.840 ;
        RECT 0.525 514.440 796.000 516.440 ;
        RECT 4.400 513.040 795.600 514.440 ;
        RECT 0.525 511.040 796.000 513.040 ;
        RECT 4.400 509.640 795.600 511.040 ;
        RECT 0.525 507.640 796.000 509.640 ;
        RECT 4.400 506.240 795.600 507.640 ;
        RECT 0.525 504.240 796.000 506.240 ;
        RECT 4.400 502.840 795.600 504.240 ;
        RECT 0.525 500.840 796.000 502.840 ;
        RECT 4.400 499.440 795.600 500.840 ;
        RECT 0.525 497.440 796.000 499.440 ;
        RECT 4.400 496.040 795.600 497.440 ;
        RECT 0.525 494.040 796.000 496.040 ;
        RECT 4.400 492.640 795.600 494.040 ;
        RECT 0.525 490.640 796.000 492.640 ;
        RECT 4.400 489.240 795.600 490.640 ;
        RECT 0.525 487.240 796.000 489.240 ;
        RECT 4.400 485.840 795.600 487.240 ;
        RECT 0.525 483.840 796.000 485.840 ;
        RECT 4.400 482.440 795.600 483.840 ;
        RECT 0.525 480.440 796.000 482.440 ;
        RECT 4.400 479.040 795.600 480.440 ;
        RECT 0.525 477.040 796.000 479.040 ;
        RECT 4.400 475.640 795.600 477.040 ;
        RECT 0.525 473.640 796.000 475.640 ;
        RECT 4.400 472.240 795.600 473.640 ;
        RECT 0.525 470.240 796.000 472.240 ;
        RECT 4.400 468.840 795.600 470.240 ;
        RECT 0.525 466.840 796.000 468.840 ;
        RECT 4.400 465.440 795.600 466.840 ;
        RECT 0.525 463.440 796.000 465.440 ;
        RECT 4.400 462.040 795.600 463.440 ;
        RECT 0.525 460.040 796.000 462.040 ;
        RECT 4.400 458.640 795.600 460.040 ;
        RECT 0.525 456.640 796.000 458.640 ;
        RECT 4.400 455.240 795.600 456.640 ;
        RECT 0.525 453.240 796.000 455.240 ;
        RECT 4.400 451.840 795.600 453.240 ;
        RECT 0.525 449.840 796.000 451.840 ;
        RECT 4.400 448.440 795.600 449.840 ;
        RECT 0.525 446.440 796.000 448.440 ;
        RECT 4.400 445.040 795.600 446.440 ;
        RECT 0.525 443.040 796.000 445.040 ;
        RECT 4.400 441.640 795.600 443.040 ;
        RECT 0.525 439.640 796.000 441.640 ;
        RECT 4.400 438.240 795.600 439.640 ;
        RECT 0.525 436.240 796.000 438.240 ;
        RECT 4.400 434.840 795.600 436.240 ;
        RECT 0.525 432.840 796.000 434.840 ;
        RECT 4.400 431.440 795.600 432.840 ;
        RECT 0.525 429.440 796.000 431.440 ;
        RECT 4.400 428.040 795.600 429.440 ;
        RECT 0.525 426.040 796.000 428.040 ;
        RECT 4.400 424.640 795.600 426.040 ;
        RECT 0.525 422.640 796.000 424.640 ;
        RECT 4.400 421.240 795.600 422.640 ;
        RECT 0.525 419.240 796.000 421.240 ;
        RECT 4.400 417.840 795.600 419.240 ;
        RECT 0.525 415.840 796.000 417.840 ;
        RECT 4.400 414.440 795.600 415.840 ;
        RECT 0.525 412.440 796.000 414.440 ;
        RECT 4.400 411.040 795.600 412.440 ;
        RECT 0.525 409.040 796.000 411.040 ;
        RECT 4.400 407.640 795.600 409.040 ;
        RECT 0.525 405.640 796.000 407.640 ;
        RECT 4.400 404.240 795.600 405.640 ;
        RECT 0.525 402.240 796.000 404.240 ;
        RECT 4.400 400.840 795.600 402.240 ;
        RECT 0.525 398.840 796.000 400.840 ;
        RECT 4.400 397.440 795.600 398.840 ;
        RECT 0.525 395.440 796.000 397.440 ;
        RECT 4.400 394.040 795.600 395.440 ;
        RECT 0.525 392.040 796.000 394.040 ;
        RECT 4.400 390.640 795.600 392.040 ;
        RECT 0.525 388.640 796.000 390.640 ;
        RECT 4.400 387.240 795.600 388.640 ;
        RECT 0.525 385.240 796.000 387.240 ;
        RECT 4.400 383.840 795.600 385.240 ;
        RECT 0.525 381.840 796.000 383.840 ;
        RECT 4.400 380.440 795.600 381.840 ;
        RECT 0.525 378.440 796.000 380.440 ;
        RECT 4.400 377.040 795.600 378.440 ;
        RECT 0.525 375.040 796.000 377.040 ;
        RECT 4.400 373.640 795.600 375.040 ;
        RECT 0.525 371.640 796.000 373.640 ;
        RECT 4.400 370.240 795.600 371.640 ;
        RECT 0.525 368.240 796.000 370.240 ;
        RECT 4.400 366.840 795.600 368.240 ;
        RECT 0.525 364.840 796.000 366.840 ;
        RECT 4.400 363.440 795.600 364.840 ;
        RECT 0.525 361.440 796.000 363.440 ;
        RECT 4.400 360.040 795.600 361.440 ;
        RECT 0.525 358.040 796.000 360.040 ;
        RECT 4.400 356.640 795.600 358.040 ;
        RECT 0.525 354.640 796.000 356.640 ;
        RECT 4.400 353.240 795.600 354.640 ;
        RECT 0.525 351.240 796.000 353.240 ;
        RECT 4.400 349.840 795.600 351.240 ;
        RECT 0.525 347.840 796.000 349.840 ;
        RECT 4.400 346.440 795.600 347.840 ;
        RECT 0.525 344.440 796.000 346.440 ;
        RECT 4.400 343.040 795.600 344.440 ;
        RECT 0.525 341.040 796.000 343.040 ;
        RECT 4.400 339.640 795.600 341.040 ;
        RECT 0.525 337.640 796.000 339.640 ;
        RECT 4.400 336.240 795.600 337.640 ;
        RECT 0.525 334.240 796.000 336.240 ;
        RECT 4.400 332.840 795.600 334.240 ;
        RECT 0.525 330.840 796.000 332.840 ;
        RECT 4.400 329.440 795.600 330.840 ;
        RECT 0.525 327.440 796.000 329.440 ;
        RECT 4.400 326.040 795.600 327.440 ;
        RECT 0.525 324.040 796.000 326.040 ;
        RECT 4.400 322.640 795.600 324.040 ;
        RECT 0.525 320.640 796.000 322.640 ;
        RECT 4.400 319.240 795.600 320.640 ;
        RECT 0.525 317.240 796.000 319.240 ;
        RECT 4.400 315.840 795.600 317.240 ;
        RECT 0.525 313.840 796.000 315.840 ;
        RECT 4.400 312.440 795.600 313.840 ;
        RECT 0.525 310.440 796.000 312.440 ;
        RECT 4.400 309.040 795.600 310.440 ;
        RECT 0.525 307.040 796.000 309.040 ;
        RECT 0.525 305.640 795.600 307.040 ;
        RECT 0.525 303.640 796.000 305.640 ;
        RECT 0.525 302.240 795.600 303.640 ;
        RECT 0.525 300.240 796.000 302.240 ;
        RECT 0.525 298.840 795.600 300.240 ;
        RECT 0.525 296.840 796.000 298.840 ;
        RECT 0.525 295.440 795.600 296.840 ;
        RECT 0.525 293.440 796.000 295.440 ;
        RECT 0.525 292.040 795.600 293.440 ;
        RECT 0.525 290.040 796.000 292.040 ;
        RECT 0.525 288.640 795.600 290.040 ;
        RECT 0.525 286.640 796.000 288.640 ;
        RECT 0.525 285.240 795.600 286.640 ;
        RECT 0.525 283.240 796.000 285.240 ;
        RECT 0.525 281.840 795.600 283.240 ;
        RECT 0.525 279.840 796.000 281.840 ;
        RECT 0.525 278.440 795.600 279.840 ;
        RECT 0.525 276.440 796.000 278.440 ;
        RECT 0.525 275.040 795.600 276.440 ;
        RECT 0.525 273.040 796.000 275.040 ;
        RECT 0.525 271.640 795.600 273.040 ;
        RECT 0.525 269.640 796.000 271.640 ;
        RECT 0.525 268.240 795.600 269.640 ;
        RECT 0.525 266.240 796.000 268.240 ;
        RECT 0.525 264.840 795.600 266.240 ;
        RECT 0.525 262.840 796.000 264.840 ;
        RECT 0.525 261.440 795.600 262.840 ;
        RECT 0.525 259.440 796.000 261.440 ;
        RECT 0.525 258.040 795.600 259.440 ;
        RECT 0.525 256.040 796.000 258.040 ;
        RECT 0.525 254.640 795.600 256.040 ;
        RECT 0.525 10.715 796.000 254.640 ;
      LAYER met4 ;
        RECT 3.975 350.375 4.305 369.065 ;
  END
END ahb_apb_bridge_top
END LIBRARY

